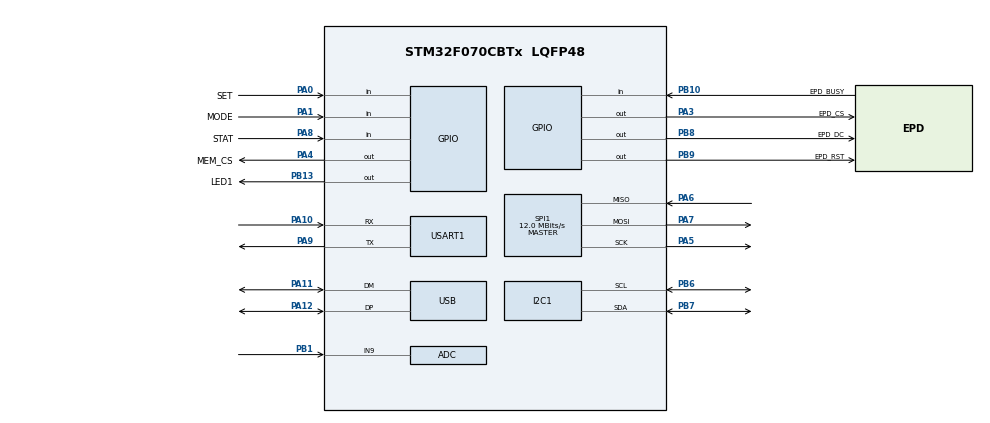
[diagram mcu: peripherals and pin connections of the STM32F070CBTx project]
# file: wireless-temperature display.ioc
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Mcu.Family=STM32F0
Mcu.Name=STM32F070CBTx
Mcu.Package=LQFP48
PA0.GPIO_Label=SET
PA0.Signal=GPIO_Input
PA1.GPIO_Label=MODE
PA1.Signal=GPIO_Input
PA10.Mode=Asynchronous
PA10.Signal=USART1_RX
PA11.Mode=Device
PA11.Signal=USB_DM
PA12.Mode=Device
PA12.Signal=USB_DP
PA13.Mode=Serial_Wire
PA13.Signal=SYS_SWDIO
PA14.Mode=Serial_Wire
PA14.Signal=SYS_SWCLK
PA3.GPIO_Label=EPD_CS
PA3.Signal=GPIO_Output
PA4.GPIO_Label=MEM_CS
PA4.Signal=GPIO_Output
PA5.Mode=Full_Duplex_Master
PA5.Signal=SPI1_SCK
PA6.Mode=Full_Duplex_Master
PA6.Signal=SPI1_MISO
PA7.Mode=Full_Duplex_Master
PA7.Signal=SPI1_MOSI
PA8.GPIO_Label=STAT
PA8.Signal=GPIO_Input
PA9.Mode=Asynchronous
PA9.Signal=USART1_TX
PB1.Mode=IN9
PB1.Signal=ADC_IN9
PB10.GPIO_Label=EPD_BUSY
PB10.Signal=GPIO_Input
PB13.GPIO_Label=LED1
PB13.Signal=GPIO_Output
PB6.Mode=I2C
PB6.Signal=I2C1_SCL
PB7.Mode=I2C
PB7.Signal=I2C1_SDA
PB8.GPIO_Label=EPD_DC
PB8.Signal=GPIO_Output
PB9.GPIO_Label=EPD_RST
PB9.Signal=GPIO_Output
PF0-OSC_IN.Mode=HSE-External-Oscillator
PF0-OSC_IN.Signal=RCC_OSC_IN
PF1-OSC_OUT.Mode=HSE-External-Oscillator
PF1-OSC_OUT.Signal=RCC_OSC_OUT
ProjectManager.HeapSize=0x200
ProjectManager.StackSize=0x400
ProjectManager.TargetToolchain=STM32CubeIDE
RCC.AHBFreq_Value=48000000
RCC.APB1Freq_Value=48000000
RCC.APB1TimFreq_Value=48000000
RCC.HCLKFreq_Value=48000000
RCC.HSE_VALUE=16000000
RCC.PLLMUL=RCC_PLL_MUL3
RCC.SYSCLKFreq_VALUE=48000000
RCC.SYSCLKSource=RCC_SYSCLKSOURCE_PLLCLK
SPI1.BaudRatePrescaler=SPI_BAUDRATEPRESCALER_4
SPI1.CalculateBaudRate=12.0 MBits/s
SPI1.Direction=SPI_DIRECTION_2LINES
SPI1.Mode=SPI_MODE_MASTER
SPI1.VirtualType=VM_MASTER
USART1.VirtualMode-Asynchronous=VM_ASYNC
board=custom

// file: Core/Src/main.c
/* USER CODE BEGIN Header */
/**
  ******************************************************************************
  * @file           : main.c
  * @brief          : Main program body
  ******************************************************************************
  * @attention
  *
  * <h2><center>&copy; Copyright (c) 2020 STMicroelectronics.
  * All rights reserved.</center></h2>
  *
  * This software component is licensed by ST under BSD 3-Clause license,
  * the "License"; You may not use this file except in compliance with the
  * License. You may obtain a copy of the License at:
  *                        opensource.org/licenses/BSD-3-Clause
  *
  ******************************************************************************
  */
/* USER CODE END Header */
#include "main.h"
#include "adc.h"
#include "i2c.h"
#include "spi.h"
#include "usart.h"
#include "usb.h"
#include "gpio.h"

/* USER CODE BEGIN Includes */
#include "EPD_Test.h"
/* USER CODE END Includes */

void SystemClock_Config(void);

int main(void)
{

  /* MCU Configuration--------------------------------------------------------*/

  /* Reset of all peripherals, Initializes the Flash interface and the Systick. */
  HAL_Init();

  /* Configure the system clock */
  SystemClock_Config();

  /* Initialize all configured peripherals */
  MX_GPIO_Init();
  MX_I2C1_Init();
  MX_SPI1_Init();
  MX_USB_PCD_Init();
  MX_ADC_Init();
  MX_USART1_UART_Init();

  /* Infinite loop */
  while (1)
  {

    /* USER CODE BEGIN 3 */
	  EPD_4in2_test();
  }
  /* USER CODE END 3 */
}

void SystemClock_Config(void)
{
  RCC_OscInitTypeDef RCC_OscInitStruct = {0};
  RCC_ClkInitTypeDef RCC_ClkInitStruct = {0};
  RCC_PeriphCLKInitTypeDef PeriphClkInit = {0};

  /** Initializes the RCC Oscillators according to the specified parameters
  * in the RCC_OscInitTypeDef structure.
  */
  RCC_OscInitStruct.OscillatorType = RCC_OSCILLATORTYPE_HSI|RCC_OSCILLATORTYPE_HSI14
                              |RCC_OSCILLATORTYPE_HSE;
  RCC_OscInitStruct.HSEState = RCC_HSE_ON;
  RCC_OscInitStruct.HSIState = RCC_HSI_ON;
  RCC_OscInitStruct.HSI14State = RCC_HSI14_ON;
  RCC_OscInitStruct.HSICalibrationValue = RCC_HSICALIBRATION_DEFAULT;
  RCC_OscInitStruct.HSI14CalibrationValue = 16;
  RCC_OscInitStruct.PLL.PLLState = RCC_PLL_ON;
  RCC_OscInitStruct.PLL.PLLSource = RCC_PLLSOURCE_HSE;
  RCC_OscInitStruct.PLL.PLLMUL = RCC_PLL_MUL6;
  RCC_OscInitStruct.PLL.PREDIV = RCC_PREDIV_DIV1;
  if (HAL_RCC_OscConfig(&RCC_OscInitStruct) != HAL_OK)
  {
    Error_Handler();
  }
  /** Initializes the CPU, AHB and APB buses clocks
  */
  RCC_ClkInitStruct.ClockType = RCC_CLOCKTYPE_HCLK|RCC_CLOCKTYPE_SYSCLK
                              |RCC_CLOCKTYPE_PCLK1;
  RCC_ClkInitStruct.SYSCLKSource = RCC_SYSCLKSOURCE_PLLCLK;
  RCC_ClkInitStruct.AHBCLKDivider = RCC_SYSCLK_DIV1;
  RCC_ClkInitStruct.APB1CLKDivider = RCC_HCLK_DIV1;

  if (HAL_RCC_ClockConfig(&RCC_ClkInitStruct, FLASH_LATENCY_1) != HAL_OK)
  {
    Error_Handler();
  }
  PeriphClkInit.PeriphClockSelection = RCC_PERIPHCLK_USB|RCC_PERIPHCLK_USART1
                              |RCC_PERIPHCLK_I2C1;
  PeriphClkInit.Usart1ClockSelection = RCC_USART1CLKSOURCE_PCLK1;
  PeriphClkInit.I2c1ClockSelection = RCC_I2C1CLKSOURCE_HSI;
  PeriphClkInit.UsbClockSelection = RCC_USBCLKSOURCE_PLL;

  if (HAL_RCCEx_PeriphCLKConfig(&PeriphClkInit) != HAL_OK)
  {
    Error_Handler();
  }
}

void Error_Handler(void)
{
}

/************************ (C) COPYRIGHT STMicroelectronics *****END OF FILE****/
